VERSION 5.8 ;
BUSBITCHARS "[]" ;
DIVIDERCHAR "/" ;
UNITS
    DATABASE MICRONS 1000 ;
END UNITS

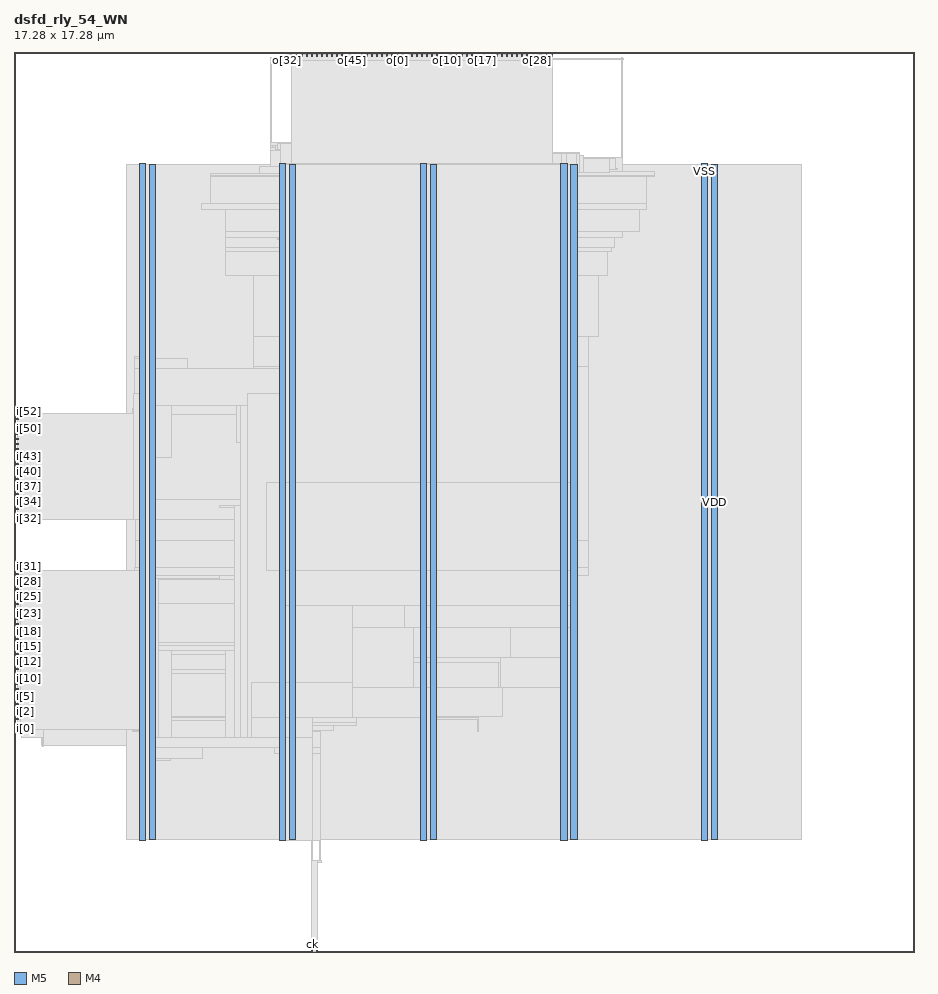
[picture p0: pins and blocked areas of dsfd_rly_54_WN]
MACRO dsfd_rly_54_WN
  FOREIGN dsfd_rly_54_WN 0 0 ;
  CLASS BLOCK ;
  SIZE 17.28 BY 17.28 ;
  PIN ck
    DIRECTION INPUT ;
    USE SIGNAL ;
    PORT
      LAYER M5 ;
        RECT  5.712 0 5.736 0.084 ;
    END
  END ck
  PIN i[0]
    DIRECTION INPUT ;
    USE SIGNAL ;
    PORT
      LAYER M4 ;
        RECT  0 4.272 0.084 4.296 ;
    END
  END i[0]
  PIN i[10]
    DIRECTION INPUT ;
    USE SIGNAL ;
    PORT
      LAYER M4 ;
        RECT  0 5.232 0.084 5.256 ;
    END
  END i[10]
  PIN i[11]
    DIRECTION INPUT ;
    USE SIGNAL ;
    PORT
      LAYER M4 ;
        RECT  0 5.328 0.084 5.352 ;
    END
  END i[11]
  PIN i[12]
    DIRECTION INPUT ;
    USE SIGNAL ;
    PORT
      LAYER M4 ;
        RECT  0 5.424 0.084 5.448 ;
    END
  END i[12]
  PIN i[13]
    DIRECTION INPUT ;
    USE SIGNAL ;
    PORT
      LAYER M4 ;
        RECT  0 5.52 0.084 5.544 ;
    END
  END i[13]
  PIN i[14]
    DIRECTION INPUT ;
    USE SIGNAL ;
    PORT
      LAYER M4 ;
        RECT  0 5.616 0.084 5.64 ;
    END
  END i[14]
  PIN i[15]
    DIRECTION INPUT ;
    USE SIGNAL ;
    PORT
      LAYER M4 ;
        RECT  0 5.712 0.084 5.736 ;
    END
  END i[15]
  PIN i[16]
    DIRECTION INPUT ;
    USE SIGNAL ;
    PORT
      LAYER M4 ;
        RECT  0 5.808 0.084 5.832 ;
    END
  END i[16]
  PIN i[17]
    DIRECTION INPUT ;
    USE SIGNAL ;
    PORT
      LAYER M4 ;
        RECT  0 5.904 0.084 5.928 ;
    END
  END i[17]
  PIN i[18]
    DIRECTION INPUT ;
    USE SIGNAL ;
    PORT
      LAYER M4 ;
        RECT  0 6 0.084 6.024 ;
    END
  END i[18]
  PIN i[19]
    DIRECTION INPUT ;
    USE SIGNAL ;
    PORT
      LAYER M4 ;
        RECT  0 6.096 0.084 6.12 ;
    END
  END i[19]
  PIN i[1]
    DIRECTION INPUT ;
    USE SIGNAL ;
    PORT
      LAYER M4 ;
        RECT  0 4.368 0.084 4.392 ;
    END
  END i[1]
  PIN i[20]
    DIRECTION INPUT ;
    USE SIGNAL ;
    PORT
      LAYER M4 ;
        RECT  0 6.192 0.084 6.216 ;
    END
  END i[20]
  PIN i[21]
    DIRECTION INPUT ;
    USE SIGNAL ;
    PORT
      LAYER M4 ;
        RECT  0 6.288 0.084 6.312 ;
    END
  END i[21]
  PIN i[22]
    DIRECTION INPUT ;
    USE SIGNAL ;
    PORT
      LAYER M4 ;
        RECT  0 6.384 0.084 6.408 ;
    END
  END i[22]
  PIN i[23]
    DIRECTION INPUT ;
    USE SIGNAL ;
    PORT
      LAYER M4 ;
        RECT  0 6.48 0.084 6.504 ;
    END
  END i[23]
  PIN i[24]
    DIRECTION INPUT ;
    USE SIGNAL ;
    PORT
      LAYER M4 ;
        RECT  0 6.576 0.084 6.6 ;
    END
  END i[24]
  PIN i[25]
    DIRECTION INPUT ;
    USE SIGNAL ;
    PORT
      LAYER M4 ;
        RECT  0 6.672 0.084 6.696 ;
    END
  END i[25]
  PIN i[26]
    DIRECTION INPUT ;
    USE SIGNAL ;
    PORT
      LAYER M4 ;
        RECT  0 6.768 0.084 6.792 ;
    END
  END i[26]
  PIN i[27]
    DIRECTION INPUT ;
    USE SIGNAL ;
    PORT
      LAYER M4 ;
        RECT  0 6.864 0.084 6.888 ;
    END
  END i[27]
  PIN i[28]
    DIRECTION INPUT ;
    USE SIGNAL ;
    PORT
      LAYER M4 ;
        RECT  0 6.96 0.084 6.984 ;
    END
  END i[28]
  PIN i[29]
    DIRECTION INPUT ;
    USE SIGNAL ;
    PORT
      LAYER M4 ;
        RECT  0 7.056 0.084 7.08 ;
    END
  END i[29]
  PIN i[2]
    DIRECTION INPUT ;
    USE SIGNAL ;
    PORT
      LAYER M4 ;
        RECT  0 4.464 0.084 4.488 ;
    END
  END i[2]
  PIN i[30]
    DIRECTION INPUT ;
    USE SIGNAL ;
    PORT
      LAYER M4 ;
        RECT  0 7.152 0.084 7.176 ;
    END
  END i[30]
  PIN i[31]
    DIRECTION INPUT ;
    USE SIGNAL ;
    PORT
      LAYER M4 ;
        RECT  0 7.248 0.084 7.272 ;
    END
  END i[31]
  PIN i[32]
    DIRECTION INPUT ;
    USE SIGNAL ;
    PORT
      LAYER M4 ;
        RECT  0 8.304 0.084 8.328 ;
    END
  END i[32]
  PIN i[33]
    DIRECTION INPUT ;
    USE SIGNAL ;
    PORT
      LAYER M4 ;
        RECT  0 8.4 0.084 8.424 ;
    END
  END i[33]
  PIN i[34]
    DIRECTION INPUT ;
    USE SIGNAL ;
    PORT
      LAYER M4 ;
        RECT  0 8.496 0.084 8.52 ;
    END
  END i[34]
  PIN i[35]
    DIRECTION INPUT ;
    USE SIGNAL ;
    PORT
      LAYER M4 ;
        RECT  0 8.592 0.084 8.616 ;
    END
  END i[35]
  PIN i[36]
    DIRECTION INPUT ;
    USE SIGNAL ;
    PORT
      LAYER M4 ;
        RECT  0 8.688 0.084 8.712 ;
    END
  END i[36]
  PIN i[37]
    DIRECTION INPUT ;
    USE SIGNAL ;
    PORT
      LAYER M4 ;
        RECT  0 8.784 0.084 8.808 ;
    END
  END i[37]
  PIN i[38]
    DIRECTION INPUT ;
    USE SIGNAL ;
    PORT
      LAYER M4 ;
        RECT  0 8.88 0.084 8.904 ;
    END
  END i[38]
  PIN i[39]
    DIRECTION INPUT ;
    USE SIGNAL ;
    PORT
      LAYER M4 ;
        RECT  0 8.976 0.084 9 ;
    END
  END i[39]
  PIN i[3]
    DIRECTION INPUT ;
    USE SIGNAL ;
    PORT
      LAYER M4 ;
        RECT  0 4.56 0.084 4.584 ;
    END
  END i[3]
  PIN i[40]
    DIRECTION INPUT ;
    USE SIGNAL ;
    PORT
      LAYER M4 ;
        RECT  0 9.072 0.084 9.096 ;
    END
  END i[40]
  PIN i[41]
    DIRECTION INPUT ;
    USE SIGNAL ;
    PORT
      LAYER M4 ;
        RECT  0 9.168 0.084 9.192 ;
    END
  END i[41]
  PIN i[42]
    DIRECTION INPUT ;
    USE SIGNAL ;
    PORT
      LAYER M4 ;
        RECT  0 9.264 0.084 9.288 ;
    END
  END i[42]
  PIN i[43]
    DIRECTION INPUT ;
    USE SIGNAL ;
    PORT
      LAYER M4 ;
        RECT  0 9.36 0.084 9.384 ;
    END
  END i[43]
  PIN i[44]
    DIRECTION INPUT ;
    USE SIGNAL ;
    PORT
      LAYER M4 ;
        RECT  0 9.456 0.084 9.48 ;
    END
  END i[44]
  PIN i[45]
    DIRECTION INPUT ;
    USE SIGNAL ;
    PORT
      LAYER M4 ;
        RECT  0 9.552 0.084 9.576 ;
    END
  END i[45]
  PIN i[46]
    DIRECTION INPUT ;
    USE SIGNAL ;
    PORT
      LAYER M4 ;
        RECT  0 9.648 0.084 9.672 ;
    END
  END i[46]
  PIN i[47]
    DIRECTION INPUT ;
    USE SIGNAL ;
    PORT
      LAYER M4 ;
        RECT  0 9.744 0.084 9.768 ;
    END
  END i[47]
  PIN i[48]
    DIRECTION INPUT ;
    USE SIGNAL ;
    PORT
      LAYER M4 ;
        RECT  0 9.84 0.084 9.864 ;
    END
  END i[48]
  PIN i[49]
    DIRECTION INPUT ;
    USE SIGNAL ;
    PORT
      LAYER M4 ;
        RECT  0 9.936 0.084 9.96 ;
    END
  END i[49]
  PIN i[4]
    DIRECTION INPUT ;
    USE SIGNAL ;
    PORT
      LAYER M4 ;
        RECT  0 4.656 0.084 4.68 ;
    END
  END i[4]
  PIN i[50]
    DIRECTION INPUT ;
    USE SIGNAL ;
    PORT
      LAYER M4 ;
        RECT  0 10.032 0.084 10.056 ;
    END
  END i[50]
  PIN i[51]
    DIRECTION INPUT ;
    USE SIGNAL ;
    PORT
      LAYER M4 ;
        RECT  0 10.128 0.084 10.152 ;
    END
  END i[51]
  PIN i[52]
    DIRECTION INPUT ;
    USE SIGNAL ;
    PORT
      LAYER M4 ;
        RECT  0 10.224 0.084 10.248 ;
    END
  END i[52]
  PIN i[53]
    DIRECTION INPUT ;
    USE SIGNAL ;
    PORT
      LAYER M4 ;
        RECT  0 10.32 0.084 10.344 ;
    END
  END i[53]
  PIN i[5]
    DIRECTION INPUT ;
    USE SIGNAL ;
    PORT
      LAYER M4 ;
        RECT  0 4.752 0.084 4.776 ;
    END
  END i[5]
  PIN i[6]
    DIRECTION INPUT ;
    USE SIGNAL ;
    PORT
      LAYER M4 ;
        RECT  0 4.848 0.084 4.872 ;
    END
  END i[6]
  PIN i[7]
    DIRECTION INPUT ;
    USE SIGNAL ;
    PORT
      LAYER M4 ;
        RECT  0 4.944 0.084 4.968 ;
    END
  END i[7]
  PIN i[8]
    DIRECTION INPUT ;
    USE SIGNAL ;
    PORT
      LAYER M4 ;
        RECT  0 5.04 0.084 5.064 ;
    END
  END i[8]
  PIN i[9]
    DIRECTION INPUT ;
    USE SIGNAL ;
    PORT
      LAYER M4 ;
        RECT  0 5.136 0.084 5.16 ;
    END
  END i[9]
  PIN o[0]
    DIRECTION OUTPUT ;
    USE SIGNAL ;
    PORT
      LAYER M5 ;
        RECT  7.344 17.196 7.368 17.28 ;
    END
  END o[0]
  PIN o[10]
    DIRECTION OUTPUT ;
    USE SIGNAL ;
    PORT
      LAYER M5 ;
        RECT  8.304 17.196 8.328 17.28 ;
    END
  END o[10]
  PIN o[11]
    DIRECTION OUTPUT ;
    USE SIGNAL ;
    PORT
      LAYER M5 ;
        RECT  8.4 17.196 8.424 17.28 ;
    END
  END o[11]
  PIN o[12]
    DIRECTION OUTPUT ;
    USE SIGNAL ;
    PORT
      LAYER M5 ;
        RECT  8.496 17.196 8.52 17.28 ;
    END
  END o[12]
  PIN o[13]
    DIRECTION OUTPUT ;
    USE SIGNAL ;
    PORT
      LAYER M5 ;
        RECT  8.592 17.196 8.616 17.28 ;
    END
  END o[13]
  PIN o[14]
    DIRECTION OUTPUT ;
    USE SIGNAL ;
    PORT
      LAYER M5 ;
        RECT  8.688 17.196 8.712 17.28 ;
    END
  END o[14]
  PIN o[15]
    DIRECTION OUTPUT ;
    USE SIGNAL ;
    PORT
      LAYER M5 ;
        RECT  8.784 17.196 8.808 17.28 ;
    END
  END o[15]
  PIN o[16]
    DIRECTION OUTPUT ;
    USE SIGNAL ;
    PORT
      LAYER M5 ;
        RECT  8.88 17.196 8.904 17.28 ;
    END
  END o[16]
  PIN o[17]
    DIRECTION OUTPUT ;
    USE SIGNAL ;
    PORT
      LAYER M5 ;
        RECT  8.976 17.196 9 17.28 ;
    END
  END o[17]
  PIN o[18]
    DIRECTION OUTPUT ;
    USE SIGNAL ;
    PORT
      LAYER M5 ;
        RECT  9.072 17.196 9.096 17.28 ;
    END
  END o[18]
  PIN o[19]
    DIRECTION OUTPUT ;
    USE SIGNAL ;
    PORT
      LAYER M5 ;
        RECT  9.168 17.196 9.192 17.28 ;
    END
  END o[19]
  PIN o[1]
    DIRECTION OUTPUT ;
    USE SIGNAL ;
    PORT
      LAYER M5 ;
        RECT  7.44 17.196 7.464 17.28 ;
    END
  END o[1]
  PIN o[20]
    DIRECTION OUTPUT ;
    USE SIGNAL ;
    PORT
      LAYER M5 ;
        RECT  9.264 17.196 9.288 17.28 ;
    END
  END o[20]
  PIN o[21]
    DIRECTION OUTPUT ;
    USE SIGNAL ;
    PORT
      LAYER M5 ;
        RECT  9.36 17.196 9.384 17.28 ;
    END
  END o[21]
  PIN o[22]
    DIRECTION OUTPUT ;
    USE SIGNAL ;
    PORT
      LAYER M5 ;
        RECT  9.456 17.196 9.48 17.28 ;
    END
  END o[22]
  PIN o[23]
    DIRECTION OUTPUT ;
    USE SIGNAL ;
    PORT
      LAYER M5 ;
        RECT  9.552 17.196 9.576 17.28 ;
    END
  END o[23]
  PIN o[24]
    DIRECTION OUTPUT ;
    USE SIGNAL ;
    PORT
      LAYER M5 ;
        RECT  9.648 17.196 9.672 17.28 ;
    END
  END o[24]
  PIN o[25]
    DIRECTION OUTPUT ;
    USE SIGNAL ;
    PORT
      LAYER M5 ;
        RECT  9.744 17.196 9.768 17.28 ;
    END
  END o[25]
  PIN o[26]
    DIRECTION OUTPUT ;
    USE SIGNAL ;
    PORT
      LAYER M5 ;
        RECT  9.84 17.196 9.864 17.28 ;
    END
  END o[26]
  PIN o[27]
    DIRECTION OUTPUT ;
    USE SIGNAL ;
    PORT
      LAYER M5 ;
        RECT  9.936 17.196 9.96 17.28 ;
    END
  END o[27]
  PIN o[28]
    DIRECTION OUTPUT ;
    USE SIGNAL ;
    PORT
      LAYER M5 ;
        RECT  10.032 17.196 10.056 17.28 ;
    END
  END o[28]
  PIN o[29]
    DIRECTION OUTPUT ;
    USE SIGNAL ;
    PORT
      LAYER M5 ;
        RECT  10.128 17.196 10.152 17.28 ;
    END
  END o[29]
  PIN o[2]
    DIRECTION OUTPUT ;
    USE SIGNAL ;
    PORT
      LAYER M5 ;
        RECT  7.536 17.196 7.56 17.28 ;
    END
  END o[2]
  PIN o[30]
    DIRECTION OUTPUT ;
    USE SIGNAL ;
    PORT
      LAYER M5 ;
        RECT  10.224 17.196 10.248 17.28 ;
    END
  END o[30]
  PIN o[31]
    DIRECTION OUTPUT ;
    USE SIGNAL ;
    PORT
      LAYER M5 ;
        RECT  10.32 17.196 10.344 17.28 ;
    END
  END o[31]
  PIN o[32]
    DIRECTION OUTPUT ;
    USE SIGNAL ;
    PORT
      LAYER M5 ;
        RECT  5.232 17.196 5.256 17.28 ;
    END
  END o[32]
  PIN o[33]
    DIRECTION OUTPUT ;
    USE SIGNAL ;
    PORT
      LAYER M5 ;
        RECT  5.328 17.196 5.352 17.28 ;
    END
  END o[33]
  PIN o[34]
    DIRECTION OUTPUT ;
    USE SIGNAL ;
    PORT
      LAYER M5 ;
        RECT  5.424 17.196 5.448 17.28 ;
    END
  END o[34]
  PIN o[35]
    DIRECTION OUTPUT ;
    USE SIGNAL ;
    PORT
      LAYER M5 ;
        RECT  5.52 17.196 5.544 17.28 ;
    END
  END o[35]
  PIN o[36]
    DIRECTION OUTPUT ;
    USE SIGNAL ;
    PORT
      LAYER M5 ;
        RECT  5.616 17.196 5.64 17.28 ;
    END
  END o[36]
  PIN o[37]
    DIRECTION OUTPUT ;
    USE SIGNAL ;
    PORT
      LAYER M5 ;
        RECT  5.712 17.196 5.736 17.28 ;
    END
  END o[37]
  PIN o[38]
    DIRECTION OUTPUT ;
    USE SIGNAL ;
    PORT
      LAYER M5 ;
        RECT  5.808 17.196 5.832 17.28 ;
    END
  END o[38]
  PIN o[39]
    DIRECTION OUTPUT ;
    USE SIGNAL ;
    PORT
      LAYER M5 ;
        RECT  5.904 17.196 5.928 17.28 ;
    END
  END o[39]
  PIN o[3]
    DIRECTION OUTPUT ;
    USE SIGNAL ;
    PORT
      LAYER M5 ;
        RECT  7.632 17.196 7.656 17.28 ;
    END
  END o[3]
  PIN o[40]
    DIRECTION OUTPUT ;
    USE SIGNAL ;
    PORT
      LAYER M5 ;
        RECT  6 17.196 6.024 17.28 ;
    END
  END o[40]
  PIN o[41]
    DIRECTION OUTPUT ;
    USE SIGNAL ;
    PORT
      LAYER M5 ;
        RECT  6.096 17.196 6.12 17.28 ;
    END
  END o[41]
  PIN o[42]
    DIRECTION OUTPUT ;
    USE SIGNAL ;
    PORT
      LAYER M5 ;
        RECT  6.192 17.196 6.216 17.28 ;
    END
  END o[42]
  PIN o[43]
    DIRECTION OUTPUT ;
    USE SIGNAL ;
    PORT
      LAYER M5 ;
        RECT  6.288 17.196 6.312 17.28 ;
    END
  END o[43]
  PIN o[44]
    DIRECTION OUTPUT ;
    USE SIGNAL ;
    PORT
      LAYER M5 ;
        RECT  6.384 17.196 6.408 17.28 ;
    END
  END o[44]
  PIN o[45]
    DIRECTION OUTPUT ;
    USE SIGNAL ;
    PORT
      LAYER M5 ;
        RECT  6.48 17.196 6.504 17.28 ;
    END
  END o[45]
  PIN o[46]
    DIRECTION OUTPUT ;
    USE SIGNAL ;
    PORT
      LAYER M5 ;
        RECT  6.576 17.196 6.6 17.28 ;
    END
  END o[46]
  PIN o[47]
    DIRECTION OUTPUT ;
    USE SIGNAL ;
    PORT
      LAYER M5 ;
        RECT  6.672 17.196 6.696 17.28 ;
    END
  END o[47]
  PIN o[48]
    DIRECTION OUTPUT ;
    USE SIGNAL ;
    PORT
      LAYER M5 ;
        RECT  6.768 17.196 6.792 17.28 ;
    END
  END o[48]
  PIN o[49]
    DIRECTION OUTPUT ;
    USE SIGNAL ;
    PORT
      LAYER M5 ;
        RECT  6.864 17.196 6.888 17.28 ;
    END
  END o[49]
  PIN o[4]
    DIRECTION OUTPUT ;
    USE SIGNAL ;
    PORT
      LAYER M5 ;
        RECT  7.728 17.196 7.752 17.28 ;
    END
  END o[4]
  PIN o[50]
    DIRECTION OUTPUT ;
    USE SIGNAL ;
    PORT
      LAYER M5 ;
        RECT  6.96 17.196 6.984 17.28 ;
    END
  END o[50]
  PIN o[51]
    DIRECTION OUTPUT ;
    USE SIGNAL ;
    PORT
      LAYER M5 ;
        RECT  7.056 17.196 7.08 17.28 ;
    END
  END o[51]
  PIN o[52]
    DIRECTION OUTPUT ;
    USE SIGNAL ;
    PORT
      LAYER M5 ;
        RECT  7.152 17.196 7.176 17.28 ;
    END
  END o[52]
  PIN o[53]
    DIRECTION OUTPUT ;
    USE SIGNAL ;
    PORT
      LAYER M5 ;
        RECT  7.248 17.196 7.272 17.28 ;
    END
  END o[53]
  PIN o[5]
    DIRECTION OUTPUT ;
    USE SIGNAL ;
    PORT
      LAYER M5 ;
        RECT  7.824 17.196 7.848 17.28 ;
    END
  END o[5]
  PIN o[6]
    DIRECTION OUTPUT ;
    USE SIGNAL ;
    PORT
      LAYER M5 ;
        RECT  7.92 17.196 7.944 17.28 ;
    END
  END o[6]
  PIN o[7]
    DIRECTION OUTPUT ;
    USE SIGNAL ;
    PORT
      LAYER M5 ;
        RECT  8.016 17.196 8.04 17.28 ;
    END
  END o[7]
  PIN o[8]
    DIRECTION OUTPUT ;
    USE SIGNAL ;
    PORT
      LAYER M5 ;
        RECT  8.112 17.196 8.136 17.28 ;
    END
  END o[8]
  PIN o[9]
    DIRECTION OUTPUT ;
    USE SIGNAL ;
    PORT
      LAYER M5 ;
        RECT  8.208 17.196 8.232 17.28 ;
    END
  END o[9]
  PIN rs
    DIRECTION INPUT ;
    USE SIGNAL ;
    PORT
      LAYER M5 ;
        RECT  5.808 0 5.832 0.084 ;
    END
  END rs
  PIN VDD
    DIRECTION INOUT ;
    USE POWER ;
    PORT
      LAYER M5 ;
        RECT  13.392 2.151 13.512 15.129 ;
        RECT  10.692 2.151 10.812 15.129 ;
        RECT  7.992 2.151 8.112 15.129 ;
        RECT  5.292 2.151 5.412 15.129 ;
        RECT  2.592 2.151 2.712 15.129 ;
    END
  END VDD
  PIN VSS
    DIRECTION INOUT ;
    USE GROUND ;
    PORT
      LAYER M5 ;
        RECT  13.2 2.137 13.32 15.143 ;
        RECT  10.5 2.137 10.62 15.143 ;
        RECT  7.8 2.137 7.92 15.143 ;
        RECT  5.1 2.137 5.22 15.143 ;
        RECT  2.4 2.137 2.52 15.143 ;
    END
  END VSS
  # OT_OBS_CLOSED layer=M5 d_um=1.536 added=6
  OBS
    LAYER RVTN ;
     RECT  2.16 2.16 15.12 2.295 ;
     RECT  2.16 2.565 15.12 2.835 ;
     RECT  2.16 3.105 15.12 3.375 ;
     RECT  2.16 3.645 15.12 3.915 ;
     RECT  2.16 4.185 15.12 4.455 ;
     RECT  2.16 4.725 15.12 4.995 ;
     RECT  2.16 5.265 15.12 5.535 ;
     RECT  2.16 5.805 15.12 6.075 ;
     RECT  2.16 6.345 15.12 6.615 ;
     RECT  2.16 6.885 15.12 7.155 ;
     RECT  2.16 7.425 15.12 7.695 ;
     RECT  2.16 7.965 15.12 8.235 ;
     RECT  2.16 8.505 15.12 8.775 ;
     RECT  2.16 9.045 15.12 9.315 ;
     RECT  2.16 9.585 15.12 9.855 ;
     RECT  2.16 10.125 15.12 10.395 ;
     RECT  2.16 10.665 15.12 10.935 ;
     RECT  2.16 11.205 15.12 11.475 ;
     RECT  2.16 11.745 15.12 12.015 ;
     RECT  2.16 12.285 15.12 12.555 ;
     RECT  2.16 12.825 15.12 13.095 ;
     RECT  2.16 13.365 15.12 13.635 ;
     RECT  2.16 13.905 15.12 14.175 ;
     RECT  2.16 14.445 15.12 14.715 ;
     RECT  2.16 14.985 15.12 15.12 ;
    LAYER RVTP ;
     RECT  2.16 2.295 15.12 2.565 ;
     RECT  2.16 2.835 15.12 3.105 ;
     RECT  2.16 3.375 15.12 3.645 ;
     RECT  2.16 3.915 15.12 4.185 ;
     RECT  2.16 4.455 15.12 4.725 ;
     RECT  2.16 4.995 15.12 5.265 ;
     RECT  2.16 5.535 15.12 5.805 ;
     RECT  2.16 6.075 15.12 6.345 ;
     RECT  2.16 6.615 15.12 6.885 ;
     RECT  2.16 7.155 15.12 7.425 ;
     RECT  2.16 7.695 15.12 7.965 ;
     RECT  2.16 8.235 15.12 8.505 ;
     RECT  2.16 8.775 15.12 9.045 ;
     RECT  2.16 9.315 15.12 9.585 ;
     RECT  2.16 9.855 15.12 10.125 ;
     RECT  2.16 10.395 15.12 10.665 ;
     RECT  2.16 10.935 15.12 11.205 ;
     RECT  2.16 11.475 15.12 11.745 ;
     RECT  2.16 12.015 15.12 12.285 ;
     RECT  2.16 12.555 15.12 12.825 ;
     RECT  2.16 13.095 15.12 13.365 ;
     RECT  2.16 13.635 15.12 13.905 ;
     RECT  2.16 14.175 15.12 14.445 ;
     RECT  2.16 14.715 15.12 14.985 ;
    LAYER M1 ;
     RECT  2.16 2.151 15.12 15.129 ;
    LAYER M2 ;
     RECT  0.103 4.392 0.139 4.41 ;
     RECT  0.139 4.122 0.499 4.41 ;
     RECT  0.499 4.122 0.535 4.518 ;
     RECT  0.535 3.96 2.16 4.518 ;
     RECT  2.16 2.151 15.12 15.129 ;
    LAYER M3 ;
     RECT  5.868 1.723 5.886 2.143 ;
     RECT  2.415 2.143 2.505 2.413 ;
     RECT  7.815 2.143 7.905 2.413 ;
     RECT  10.515 2.143 10.605 2.413 ;
     RECT  13.215 2.143 13.305 2.413 ;
     RECT  2.415 2.413 2.697 3.685 ;
     RECT  2.415 3.685 3.006 3.721 ;
     RECT  5.115 2.143 5.886 3.811 ;
     RECT  2.415 3.721 3.618 3.919 ;
     RECT  5.004 3.811 5.886 3.919 ;
     RECT  0.54 3.955 0.558 4.117 ;
     RECT  2.415 3.919 5.886 4.225 ;
     RECT  2.268 4.225 5.886 4.261 ;
     RECT  2.268 4.261 6.138 4.351 ;
     RECT  0.144 4.117 0.558 4.387 ;
     RECT  2.268 4.351 6.57 4.397 ;
     RECT  7.815 2.413 8.097 4.459 ;
     RECT  8.892 4.225 8.91 4.459 ;
     RECT  2.304 4.397 6.57 4.495 ;
     RECT  7.815 4.459 8.91 4.495 ;
     RECT  2.304 4.495 8.91 4.531 ;
     RECT  0.108 4.387 0.558 4.685 ;
     RECT  0.144 4.685 0.558 4.877 ;
     RECT  0.504 4.877 0.558 4.973 ;
     RECT  0.504 4.973 0.522 5.165 ;
     RECT  2.304 4.531 9.378 5.341 ;
     RECT  2.304 5.341 9.558 5.419 ;
     RECT  2.268 5.419 9.558 5.881 ;
     RECT  2.268 5.881 9.594 5.933 ;
     RECT  2.304 5.933 9.594 6.691 ;
     RECT  10.515 2.413 10.797 6.691 ;
     RECT  0.432 6.955 0.45 7.051 ;
     RECT  0.36 7.051 0.45 7.133 ;
     RECT  0.36 7.133 0.378 7.181 ;
     RECT  2.304 6.691 10.797 7.231 ;
     RECT  2.304 7.231 11.034 7.385 ;
     RECT  2.34 7.385 11.034 7.901 ;
     RECT  2.34 7.901 9.558 8.299 ;
     RECT  2.304 8.299 9.558 8.683 ;
     RECT  0.144 9.499 0.162 9.677 ;
     RECT  2.268 8.683 9.558 10.427 ;
     RECT  2.304 10.427 9.558 11.201 ;
     RECT  4.608 11.201 9.558 11.245 ;
     RECT  10.296 7.901 11.034 11.245 ;
     RECT  2.304 11.201 3.33 11.399 ;
     RECT  2.304 11.399 2.697 11.435 ;
     RECT  4.608 11.245 11.034 11.821 ;
     RECT  4.608 11.821 11.214 12.991 ;
     RECT  4.068 12.991 11.394 13.441 ;
     RECT  4.068 13.441 11.466 13.531 ;
     RECT  4.068 13.531 11.538 13.711 ;
     RECT  4.068 13.711 11.682 13.837 ;
     RECT  4.068 13.837 12.006 14.251 ;
     RECT  3.6 14.251 12.15 14.369 ;
     RECT  2.415 11.435 2.697 14.867 ;
     RECT  13.215 2.413 13.497 14.867 ;
     RECT  3.78 14.369 12.15 14.881 ;
     RECT  3.78 14.881 12.294 14.909 ;
     RECT  3.78 14.909 9.162 14.945 ;
     RECT  10.26 14.909 12.294 14.981 ;
     RECT  4.716 14.945 9.162 15.089 ;
     RECT  2.415 14.867 2.505 15.137 ;
     RECT  13.215 14.867 13.305 15.137 ;
     RECT  10.26 14.981 11.682 15.245 ;
     RECT  10.26 15.245 10.926 15.293 ;
     RECT  10.26 15.293 10.854 15.341 ;
     RECT  4.932 15.089 9.162 15.389 ;
     RECT  10.26 15.341 10.278 15.389 ;
     RECT  4.932 15.389 8.334 15.437 ;
     RECT  4.932 15.437 6.138 15.485 ;
     RECT  4.932 15.485 6.102 15.533 ;
     RECT  5.688 15.533 6.102 15.965 ;
     RECT  6.876 15.437 8.334 17.117 ;
     RECT  9.072 15.389 9.162 17.117 ;
     RECT  4.932 15.533 4.95 17.165 ;
     RECT  6.084 15.965 6.102 17.165 ;
     RECT  6.876 17.117 6.894 17.165 ;
     RECT  7.632 17.117 8.334 17.165 ;
     RECT  9.072 17.117 9.09 17.165 ;
     RECT  11.664 15.245 11.682 17.165 ;
    LAYER M4 ;
     RECT  0.06 4.272 0.133 7.272 ;
     RECT  0.06 8.304 2.293 10.344 ;
     RECT  0.133 4.272 2.408 7.32 ;
     RECT  2.293 8.304 2.408 10.728 ;
     RECT  2.408 2.148 2.512 15.132 ;
     RECT  2.512 2.418 2.704 14.862 ;
     RECT  2.704 4.128 2.765 7.176 ;
     RECT  2.765 4.128 3.017 5.784 ;
     RECT  2.704 9.504 3.017 10.488 ;
     RECT  2.765 7.152 3.949 7.176 ;
     RECT  3.017 4.128 4.057 4.44 ;
     RECT  3.017 5.712 4.057 5.784 ;
     RECT  4.057 4.128 4.237 5.784 ;
     RECT  3.949 7.152 4.237 7.224 ;
     RECT  3.949 8.544 4.237 8.568 ;
     RECT  3.017 10.32 4.273 10.488 ;
     RECT  4.237 4.128 4.345 8.568 ;
     RECT  4.273 9.792 4.345 10.488 ;
     RECT  4.345 4.128 4.489 10.488 ;
     RECT  4.957 15.456 5.029 15.48 ;
     RECT  5.029 15.408 5.065 15.48 ;
     RECT  4.489 4.128 5.108 10.728 ;
     RECT  5.065 13.68 5.108 13.704 ;
     RECT  5.065 15.408 5.108 15.528 ;
     RECT  5.108 2.148 5.404 15.528 ;
     RECT  5.404 13.632 5.677 15.528 ;
     RECT  5.797 1.728 5.897 1.752 ;
     RECT  5.677 13.632 6.041 15.96 ;
     RECT  6.041 14.208 6.131 15.96 ;
     RECT  6.131 14.208 6.257 15.48 ;
     RECT  6.257 14.352 6.515 15.48 ;
     RECT  5.404 4.416 6.581 10.728 ;
     RECT  6.581 4.704 6.707 10.728 ;
     RECT  5.404 12.528 6.757 12.552 ;
     RECT  6.515 14.352 6.833 15.384 ;
     RECT  4.921 17.136 6.939 17.16 ;
     RECT  6.757 11.856 7.237 12.552 ;
     RECT  6.939 17.088 7.405 17.16 ;
     RECT  7.237 11.76 7.477 12.552 ;
     RECT  6.833 14.352 7.477 14.856 ;
     RECT  7.405 16.56 7.525 17.16 ;
     RECT  7.525 16.464 7.763 17.16 ;
     RECT  6.707 4.704 7.808 8.568 ;
     RECT  6.707 9.6 7.808 10.728 ;
     RECT  7.477 11.76 7.808 14.856 ;
     RECT  7.808 2.148 7.912 15.132 ;
     RECT  7.912 2.418 8.104 15.132 ;
     RECT  8.104 6.576 8.165 8.472 ;
     RECT  8.104 9.6 8.243 9.624 ;
     RECT  8.104 11.376 8.243 15.132 ;
     RECT  7.763 16.896 8.243 17.16 ;
     RECT  8.165 7.344 8.284 8.472 ;
     RECT  8.243 16.992 8.291 17.16 ;
     RECT  8.243 11.76 8.389 15.132 ;
     RECT  8.291 17.088 9.101 17.16 ;
     RECT  8.389 11.76 9.205 15.384 ;
     RECT  8.104 5.568 9.269 5.592 ;
     RECT  9.269 5.088 9.353 5.592 ;
     RECT  9.205 11.376 9.425 15.384 ;
     RECT  9.101 17.088 9.541 17.112 ;
     RECT  9.493 5.664 9.565 5.688 ;
     RECT  9.541 16.512 10.019 17.112 ;
     RECT  9.425 11.952 10.289 15.384 ;
     RECT  9.565 5.664 10.508 6.264 ;
     RECT  8.284 7.344 10.508 8.184 ;
     RECT  10.289 11.952 10.508 15.336 ;
     RECT  10.508 2.148 10.612 15.336 ;
     RECT  10.612 2.418 10.804 15.336 ;
     RECT  10.804 14.976 10.865 15.336 ;
     RECT  10.865 14.976 10.937 15.288 ;
     RECT  10.937 14.976 11.441 15.24 ;
     RECT  11.441 15.024 11.549 15.24 ;
     RECT  11.549 15.024 11.585 15.048 ;
     RECT  10.117 17.136 11.693 17.16 ;
     RECT  13.208 2.148 13.312 15.132 ;
     RECT  13.312 2.418 13.504 14.862 ;
    LAYER M5 ;
     RECT  5.712 0.016 5.832 1.763 ;
     RECT  5.712 1.763 5.736 2.137 ;
     RECT  2.4 2.137 2.52 2.151 ;
     RECT  7.8 2.137 7.92 2.151 ;
     RECT  10.5 2.137 10.62 2.151 ;
     RECT  13.2 2.137 13.32 2.151 ;
     RECT  5.1 2.137 5.736 4.117 ;
     RECT  4.56 4.117 5.736 4.501 ;
     RECT  7.8 2.151 8.112 5.077 ;
     RECT  4.56 4.501 6.504 5.171 ;
     RECT  7.68 5.077 8.112 5.557 ;
     RECT  9.312 5.077 9.336 5.557 ;
     RECT  7.68 5.557 9.336 5.653 ;
     RECT  7.68 5.653 9.528 6.229 ;
     RECT  10.5 2.151 10.812 6.229 ;
     RECT  5.1 5.171 6.504 6.661 ;
     RECT  7.488 6.229 10.812 6.661 ;
     RECT  0.144 7.141 0.168 7.331 ;
     RECT  5.1 6.661 10.812 7.333 ;
     RECT  4.848 7.333 10.812 9.011 ;
     RECT  2.4 2.151 2.712 15.129 ;
     RECT  5.1 9.011 10.812 15.129 ;
     RECT  13.2 2.151 13.512 15.129 ;
     RECT  2.4 15.129 2.52 15.143 ;
     RECT  5.1 15.129 10.62 15.143 ;
     RECT  13.2 15.129 13.32 15.143 ;
     RECT  5.328 15.143 10.344 17.125 ;
     RECT  5.232 17.125 10.344 17.232 ;
     RECT  6.504 4.501 7.8 5.077 ;
     RECT  6.504 5.077 7.68 6.229 ;
     RECT  8.112 5.077 9.312 5.557 ;
     RECT  9.336 5.077 10.5 5.653 ;
     RECT  9.528 5.653 10.5 6.229 ;
     RECT  6.504 6.229 7.488 6.661 ;
  END
END dsfd_rly_54_WN
END LIBRARY
